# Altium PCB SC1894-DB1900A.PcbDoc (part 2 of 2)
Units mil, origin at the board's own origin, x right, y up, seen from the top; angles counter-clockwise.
Board outline 1800 x 1000 mil, 4 copper layers (L1 TOP, L2 GND, L3 PWR, L4  BOT), stack 35.4 mil thick; 130 components, 74 nets, 300 pads, 606 vias.

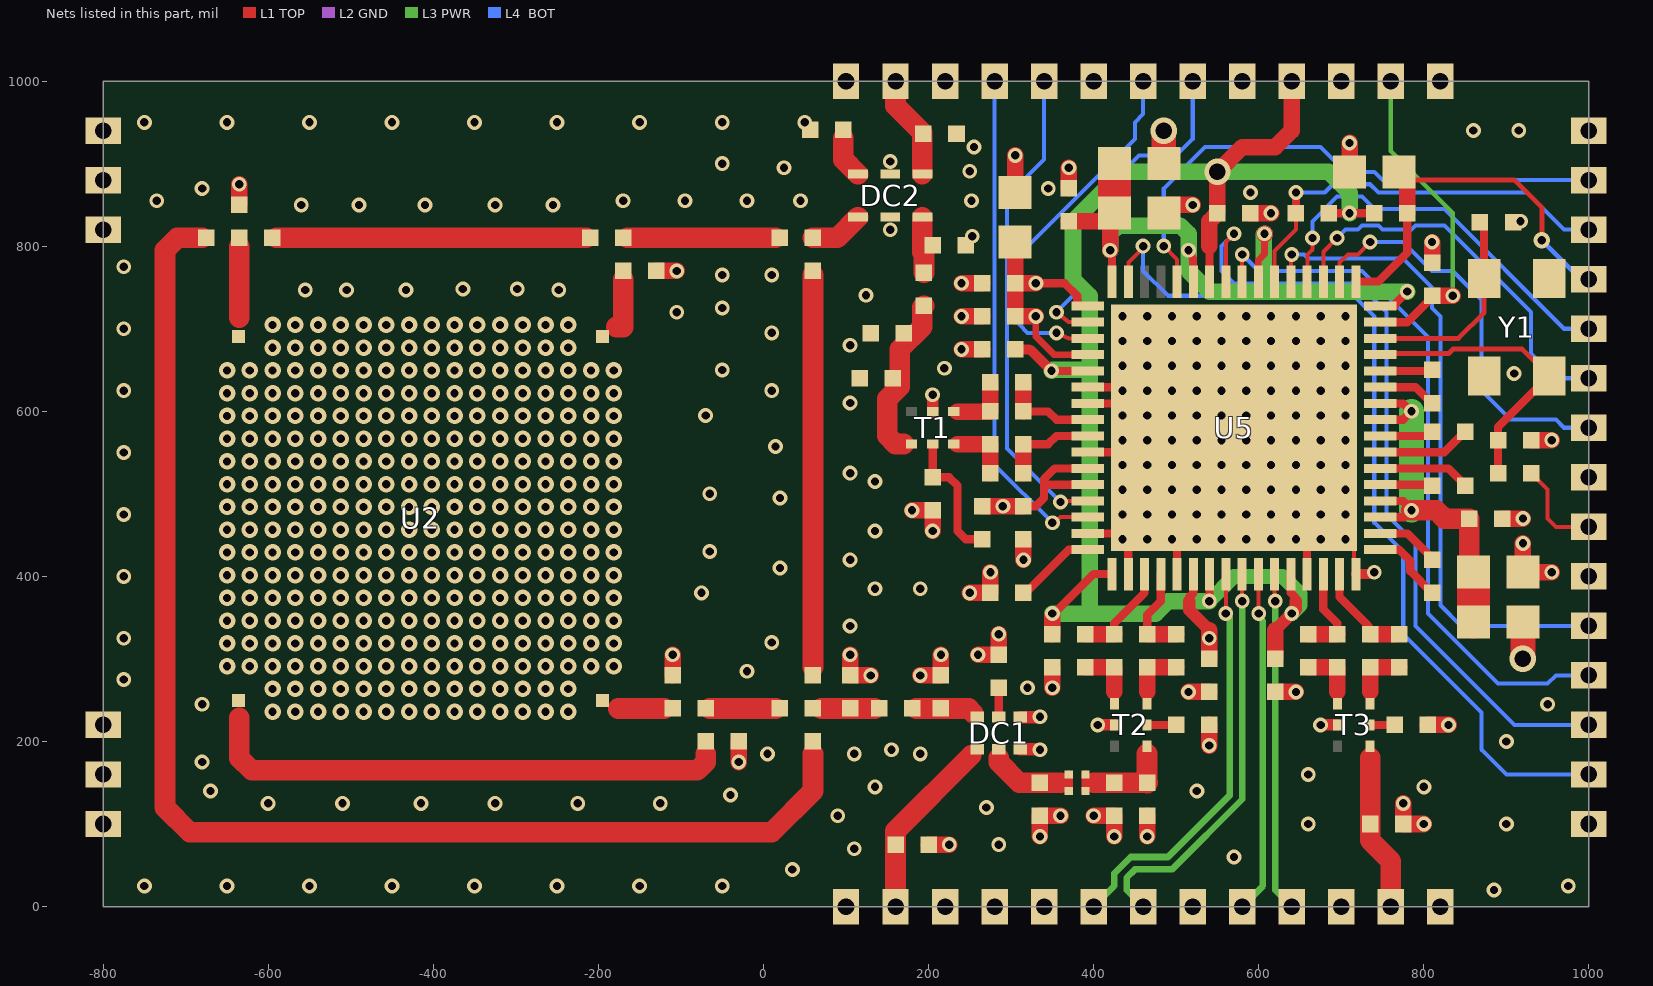
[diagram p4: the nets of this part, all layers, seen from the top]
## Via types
v1: diameter 20, hole 10, L1 TOP to L4  BOT, tented both sides, 308 vias
v2: diameter 18/18/18/18 (per signal layer), hole 10, L1 TOP to L4  BOT, tented both sides, 194 vias
v3: diameter 18/18/18/18 (per signal layer), hole 10, L1 TOP to L4  BOT, 100 vias
v4: diameter 32/32/32/32 (per signal layer), hole 20, L1 TOP to L4  BOT, tented both sides, 3 vias
v5: diameter 20/20/20/20 (per signal layer), hole 10, L1 TOP to L4  BOT, tented both sides, 1 vias

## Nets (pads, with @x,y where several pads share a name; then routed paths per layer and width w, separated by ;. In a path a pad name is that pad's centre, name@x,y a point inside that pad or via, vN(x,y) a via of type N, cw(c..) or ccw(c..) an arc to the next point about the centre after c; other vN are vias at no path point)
+1.8V: C6.1 C8.1 C9.1 C12.1 C31.1 C34.1 FT1.2 FT2.1 FT3.1 P30.1 U5.1 U5.4 U5.11 U5.12 U5.22 U5.47 | length 1125
  L1 TOP w5: C8.1@810,740 C8.1@812.05,740
  L1 TOP w8: v2(330,715) 330,690.58 352,668.58 U5.4@392.83,668.58
  L1 TOP w10: C31.1@315,485 330,485 340,495 340,511.1 ; v2(330,755) 365,755 380,740 380,727.64 U5.1@392.83,727.64 ; U5.12@392.83,511.1 340,511.1 ; U5.11@392.83,530.79 352.8,530.79 340,517.99 340,511.1 ; 515.79,370 515.79,375 520.79,380 U5.22@520.79,402.83 ; U5.47@747.17,707.95 780,707.95 C8.1@812.05,740
  L1 TOP w15: 515.79,370 515.79,359.21 540,335
  L1 TOP w20: FT3.1@265,485 v2(290,485) C31.1@315,485 ; C6.1@305,805 C9.1@305,755 ; v2(330,715) C12.1@305,715 C9.1@305,755 ; v2(330,755) C9.1@305,755 ; C34.1@540,300 v2(540,325) 540,335 ; C8.1@812.05,740 v2(835,740)
  L1 TOP w30: FT1.2@485,900 v4(485,940) ; v4(920,300) FT2.1@920,345
  L3 PWR w5: P30.1@760,1000 760,915 835,840 v2(835,740)
+3.3V: C3.2 C14.1 C33.1 C35.1 P32.1 R1.2 R2.1 U5.5 U5.17 U5.23 U5.28 U5.58 | length 2007.7
  L1 TOP w10: v2(349,649) 349.1,648.9 U5.5@392.83,648.9 ; v2@350,352.49 v2(350,355) 352.17,355 400,402.83 U5.17@422.36,402.83 ; v2(540,370) 540.47,370.47 U5.23@540.47,402.83 ; 540,800 540.47,799.53 U5.58@540.47,757.17 ; U5.28@638.9,402.83 638.9,380 645,373.9 645,370 ; R1.2@685,840 v2(710,840) R2.1@740,840
  L1 TOP w12: C14.1@305,675 321.34,675 322.17,674.17 323.83,674.17 v2(349,649)
  L1 TOP w15: 620,335 v2(640,355) 645,360 645,370
  L1 TOP w20: C33.1@350,330 v2@350,352.49 ; 540,800 540,830 C3.2@550,840 v4(550,890) 580,920 620,920 640,940 P32.1@640,1000 ; C35.1@620,300 620,335
  L3 PWR w18: v2(540,370) 570,400 628.75,400 650,378.75 650,365 v2(640,355)
  L3 PWR w20: v2(349,649) 350,650 395,650 ; v2(350,355) 395,355 ; v2(540,370) 490,370 475,355 395,355 ; v2(710,840) 710,865 685,890 v4(550,890) 435,890 375,830 375,760 395,740 395,650 ; 395,355 395,650
ADCIN0N: P7.1 U5.25 | length 495.6
  L1 TOP w5: U5.25@579.84,402.83 579.84,370 v2(580,370)
  L3 PWR w8: P7.1@460,0 440,20 440,35 450,45 495,45 580,130 v2(580,370)
ADCIN0P: P6.1 U5.24 | length 499.8
  L1 TOP w5: v2(560,355) 560.16,355 U5.24@560.16,402.83
  L3 PWR w8: P6.1@400,0 425,25 425,40 445,60 490,60 565,135 565,350 v2(560,355)
ADCIN1N: P10.1 U5.27 | length 411.9
  L1 TOP w5: U5.27@619.21,402.83 619.21,370 v2(620,370)
  L3 PWR w8: v2(620,370) 620,20 P10.1@640,0
ADCIN1P: P9.1 U5.26 | length 414.8
  L1 TOP w5: U5.26@599.53,402.83 599.53,355 v2(600,355)
  L3 PWR w8: P9.1@580,0 605,25 605,345 v2(600,355)
DGPIN0: P15.1 U5.63 | length 1104.3
  L1 TOP w5: U5.63@442.05,757.17 442.05,780 460,797.95 v2(460,800)
  L4  BOT w5: v2(460,800) 460,770 490,740 715,740 740,715 740,465 775,430 775,330 870,235 870,190 900,160 P15.1@1000,160
DGPIN1: P17.1 U5.56 | length 868.8
  L1 TOP w5: U5.56@579.84,757.17 579.84,790 v2(580,790)
  L4  BOT w5: v2(580,790) 600,770 725,770 805,690 805,355 890,270 950,270 960,280 P17.1@1000,280
EXTCLKIN: C15.2 P20.1 | length 117.4
  L1 TOP w5: C15.2@930,525 950,505 950,470 960,460 P20.1@1000,460
GND: C1.2 C2.1 C3.1 C4.2 C6.2 C8.2 C9.2 C10.2 C11.2 C12.2 C14.2 C22.2 C26.1 C28.1 C29.2 C30.2 C31.2 C33.2 C34.2 C35.2 C36.2 C45.2 C46.2 C47.2 C48.2 DC1.3 DC1.4 DC2.2 DC2.5 P1.1 P3.1 P4.1 P5.1 P8.1 P11.1 P13.1 P14.1 P19.1 P21.1 P28.1 P29.1 P31.1 P33.1 P36.1 P39.1 P41.1 P42.1 P43.1 P44.1 P45.1 P46.1 P47.1 R10.2 R12.1 R13.1 R15.2 R16.2 R21.1 R23.2 R25.2 R27.1 R98.1 R99.1 R104.1 R105.1 T1.5 T2.5 T3.5 U5.6 U5.7 U5.10 U5.15 U5.18 U5.21 U5.29 U5.32 U5.65 Y1.2 Y1.4 | length 2672.5
  L1 TOP w5: v3(705,445) 715.47,445 715.47,405 U5.32@717.64,402.83
  L1 TOP w10: U5.15@392.83,452.05 U5.65@442.05,452.05 ; U5.10@392.83,550.47 U5.65@442.05,550.47 ; U5.7@392.83,609.53 U5.65@570,609.53 ; U5.6@392.83,629.21 495,629.21 570,629.21 U5.65@570,609.53 ; U5.18@442.05,402.83 U5.65@442.05,452.05 ; U5.21@501.1,402.83 U5.65@501.1,452.05 ; U5.29@658.58,402.83 658.58,580 U5.65@570,580 ; U5.65@442.05,452.05 U5.65@501.1,452.05 ; U5.65@442.05,452.05 U5.65@442.05,550.47 ; U5.65@442.05,550.47 U5.65@501.1,550.47 ; U5.65@501.1,452.05 U5.65@501.1,550.47 ; U5.65@501.1,550.47 570,550.47 U5.65@570,580 ; U5.65@501.1,550.47 501.1,580 U5.65@570,580 ; U5.65@570,580 U5.65@570,609.53
  L1 TOP w12: U5.32@717.64,402.83 737.83,402.83 v2(740,405)
  L1 TOP w14: T1.5@205,599.68 v2(205,620) ; v2(405,220) T2.5@425.32,220 ; v2(675,220) T3.5@695.32,220
  L1 TOP w15: DC1.3@310.98,190.51 334.49,190.51 v2(335,190) ; DC1.4@310.98,229.49 334.49,229.49 v2(335,230)
  L1 TOP w20: R98.1@-635,850 v2(-635,875) ; R105.1@-130,770 v2(-105,770) ; R104.1@-110,280 v2(-110,305) ; v2(-30,175) R99.1@-30,200 ; v2(105,305) R13.1@105,280 v2(130,280) ; v2(180,480) C26.1@205,480 v2(205,455) ; v2(190,280) R15.2@215,280 v2(215,305) ; C47.2@200,75 v2(225,75) ; v2(240,675) C14.2@265,675 ; v2(240,715) C12.2@265,715 ; v2(240,755) C9.2@265,755 ; v2(250,380) R12.1@275,380 v2(275,405) ; v2(260,305) R16.2@285,305 v2(285,330) ; C6.2@305,865 v2(305,910) ; v2(315,420) C31.2@315,445 ; v2(335,85) R21.1@335,110 v2(360,110) ; v2(350,265) C33.2@350,290 ; C4.2@370,870 v2(370,895) ; v2(400,110) R23.2@425,110 v2(425,85) ; v2(465,85) C46.2@465,110 ; C2.1@485,840 485,850 v2(520,850) ; v2(515,260) C34.2@540,260 ; v2(540,195) C28.1@540,220 ; C3.1@590,840 v2(615,840) ; C35.2@620,260 v2(645,260) ; C1.2@710,890 v2(710,925) ; v2(775,125) C45.2@775,100 v2(800,100) ; C36.2@805,220 v2(830,220) ; C8.2@810,780 v2(810,805) ; C29.2@895,470 v2(920,470) ; v2(920,440) C30.2@920,405 v2(955,405) ; C11.2@930,565 v2(955,565)
  L2 GND w20: P1.1@100,0 100,1.81 P1.1@100.69,2.5 ; P3.1@219.7,2.5 220,2.2 P3.1@220,0 ; P31.1@700,999.24 P31.1@701.74,997.5 ; P13.1@820,2.33 P13.1@820.17,2.5
  L3 PWR w20: P1.1@100,0 100,1.94 P1.1@100.56,2.5 ; P3.1@220,0 P3.1@220,2.5
  other v1: -594.72,236.06 -567.17,236.06 -539.61,236.06 -512.05,236.06 -484.49,236.06 -456.93,236.06 -429.37,236.06 -401.81,236.06 -374.25,236.06 -346.69,236.06 -319.13,236.06 -291.57,236.06 -264.02,236.06 -236.46,236.06 -594.72,263.62 -567.17,263.62 -539.61,263.62 -512.05,263.62 -484.49,263.62 -456.93,263.62 -429.37,263.62 -401.81,263.62 -374.25,263.62 -346.69,263.62 -319.13,263.62 -291.57,263.62 -264.02,263.62 -236.46,263.62 -649.84,291.18 -622.28,291.18 -594.72,291.18 -567.17,291.18 -539.61,291.18 -512.05,291.18 -484.49,291.18 -456.93,291.18 -429.37,291.18 -401.81,291.18 -374.25,291.18 -346.69,291.18 -319.13,291.18 -291.57,291.18 -264.02,291.18 -236.46,291.18 -208.9,291.18 -181.34,291.18 -649.84,318.74 -622.28,318.74 -594.72,318.74 -567.17,318.74 -539.61,318.74 -512.05,318.74 -484.49,318.74 -456.93,318.74 -429.37,318.74 -401.81,318.74 -374.25,318.74 -346.69,318.74 -319.13,318.74 -291.57,318.74 -264.02,318.74 -236.46,318.74 -208.9,318.74 -181.34,318.74 -649.84,346.3 -622.28,346.3 -594.72,346.3 -567.17,346.3 -539.61,346.3 -512.05,346.3 -484.49,346.3 -456.93,346.3 -429.37,346.3 -401.81,346.3 -374.25,346.3 -346.69,346.3 -319.13,346.3 -291.57,346.3 -264.02,346.3 -236.46,346.3 -208.9,346.3 -181.34,346.3 -649.84,373.86 -622.28,373.86 -594.72,373.86 -567.17,373.86 -539.61,373.86 -512.05,373.86 -484.49,373.86 -456.93,373.86 -429.37,373.86 -401.81,373.86 -374.25,373.86 -346.69,373.86 -319.13,373.86 -291.57,373.86 -264.02,373.86 -236.46,373.86 -208.9,373.86 -181.34,373.86 -649.84,401.42 -622.28,401.42 -594.72,401.42 -567.17,401.42 -539.61,401.42 -512.05,401.42 -484.49,401.42 -456.93,401.42 -429.37,401.42 -401.81,401.42 -374.25,401.42 -346.69,401.42 -319.13,401.42 -291.57,401.42 -264.02,401.42 -236.46,401.42 -208.9,401.42 -181.34,401.42 -649.84,428.98 -622.28,428.98 -594.72,428.98 -567.17,428.98 -539.61,428.98 -512.05,428.98 -484.49,428.98 -456.93,428.98 -429.37,428.98 -401.81,428.98 -374.25,428.98 -346.69,428.98 -319.13,428.98 -291.57,428.98 -264.02,428.98 -236.46,428.98 -208.9,428.98 -181.34,428.98 -649.84,456.54 -622.28,456.54 -594.72,456.54 -567.17,456.54 -539.61,456.54 -512.05,456.54 -484.49,456.54 -456.93,456.54 -429.37,456.54 -401.81,456.54 -374.25,456.54 -346.69,456.54 -319.13,456.54 -291.57,456.54 -264.02,456.54 -236.46,456.54 -208.9,456.54 -181.34,456.54 -649.84,484.09 -622.28,484.09 -594.72,484.09 -567.17,484.09 -539.61,484.09 -512.05,484.09 -484.49,484.09 -456.93,484.09 -429.37,484.09 -401.81,484.09 -374.25,484.09 -346.69,484.09 -319.13,484.09 -291.57,484.09 -264.02,484.09 -236.46,484.09 -208.9,484.09 -181.34,484.09 -649.84,511.65 -622.28,511.65 -594.72,511.65 -567.17,511.65 -539.61,511.65 -512.05,511.65 -484.49,511.65 -456.93,511.65 -429.37,511.65 -401.81,511.65 -374.25,511.65 -346.69,511.65 -319.13,511.65 -291.57,511.65 -264.02,511.65 -236.46,511.65 -208.9,511.65 -181.34,511.65 -649.84,539.21 -622.28,539.21 -594.72,539.21 -567.17,539.21 -539.61,539.21 -512.05,539.21 -484.49,539.21 -456.93,539.21 -429.37,539.21 -401.81,539.21 -374.25,539.21 -346.69,539.21 -319.13,539.21 -291.57,539.21 -264.02,539.21 -236.46,539.21 -208.9,539.21 -181.34,539.21 -649.84,566.77 -622.28,566.77 -594.72,566.77 -567.17,566.77 -539.61,566.77 -512.05,566.77 -484.49,566.77 -456.93,566.77 -429.37,566.77 -401.81,566.77 -374.25,566.77 -346.69,566.77 -319.13,566.77 -291.57,566.77 -264.02,566.77 -236.46,566.77 -208.9,566.77 -181.34,566.77 -649.84,594.33 -622.28,594.33 -594.72,594.33 -567.17,594.33 -539.61,594.33 -512.05,594.33 -484.49,594.33 -456.93,594.33 -429.37,594.33 -401.81,594.33 -374.25,594.33 -346.69,594.33 -319.13,594.33 -291.57,594.33 -264.02,594.33 -236.46,594.33 -208.9,594.33 -181.34,594.33 -649.84,621.89 -622.28,621.89 -594.72,621.89 -567.17,621.89 -539.61,621.89 -512.05,621.89 -484.49,621.89 -456.93,621.89 -429.37,621.89 -401.81,621.89 -374.25,621.89 -346.69,621.89 -319.13,621.89 -291.57,621.89 -264.02,621.89 -236.46,621.89 -208.9,621.89 -181.34,621.89 -649.84,649.45 -622.28,649.45 -594.72,649.45 -567.17,649.45 -539.61,649.45 -512.05,649.45 -484.49,649.45 -456.93,649.45 -429.37,649.45 -401.81,649.45 -374.25,649.45 -346.69,649.45 -319.13,649.45 -291.57,649.45 -264.02,649.45 -236.46,649.45 -208.9,649.45 -181.34,649.45 -594.72,677.01 -567.17,677.01 -539.61,677.01 -512.05,677.01 -484.49,677.01 -456.93,677.01 -429.37,677.01 -401.81,677.01 -374.25,677.01 -346.69,677.01 -319.13,677.01 -291.57,677.01 -264.02,677.01 -236.46,677.01 -594.72,704.57 -567.17,704.57 -539.61,704.57 -512.05,704.57 -484.49,704.57 -456.93,704.57 -429.37,704.57 -401.81,704.57 -374.25,704.57 -346.69,704.57 -319.13,704.57 -291.57,704.57 -264.02,704.57 -236.46,704.57
  other v2: 885,20 -750,25 -650,25 -550,25 -450,25 -350,25 -250,25 -150,25 -50,25 975,25 35,45 570,60 110,70 285,75 660,100 900,100 90,110 270,120 -600,125 -510,125 -415,125 -325,125 -225,125 -125,125 -40,135 -670,140 525,140 135,145 800,145 660,160 -680,175 5,185 110,185 190,185 155,190 900,200 -680,245 950,245 320,265 -775,275 -20,285 10,320 -775,325 105,340 -75,380 135,385 190,385 -775,400 20,410 105,420 -65,430 135,455 -775,475 20,495 -65,500 135,515 105,525 -775,550 14.69,557.28 -70,595 105,610 -775,625 10,625 909.45,645.67 -50,650 219.17,652.05 105,680 10,695 -775,700 -105,720 -50,725 124.09,740.59 -555.12,747.05 -504.92,747.05 -433.07,747.05 -248.03,747.05 -364.17,748.03 -298.23,748.03 -50,765 10,765 -775,775 252.95,812.01 153.54,819.88 917.24,830.16 -560,850 -490,850 -410,850 -325,850 -255,850 -735,855 -170,855 -95,855 -20,855 45,855 252.05,855.08 590,865 -680,870 345,870 250,890.75 25,895 -50,900 153.54,902.56 255,920 860,940 915,940 -750,950 -650,950 -550,950 -450,950 -350,950 -250,950 -150,950 -50,950 50,950
  other v3: 435,445 465,445 495,445 525,445 555,445 585,445 615,445 645,445 675,445 435,475 465,475 495,475 525,475 555,475 585,475 615,475 645,475 675,475 705,475 435,505 465,505 495,505 525,505 555,505 585,505 615,505 645,505 675,505 705,505 435,535 465,535 495,535 525,535 555,535 585,535 615,535 645,535 675,535 705,535 435,565 465,565 495,565 525,565 555,565 585,565 615,565 645,565 675,565 705,565 435,595 465,595 495,595 525,595 555,595 585,595 615,595 645,595 675,595 705,595 435,625 465,625 495,625 525,625 555,625 585,625 615,625 645,625 675,625 705,625 435,655 465,655 495,655 525,655 555,655 585,655 615,655 645,655 675,655 705,655 435,685 465,685 495,685 525,685 555,685 585,685 615,685 645,685 675,685 705,685 435,715 465,715 495,715 525,715 555,715 585,715 615,715 645,715 675,715 705,715
LOADENB: P27.1 U5.60 | length 671.8
  L1 TOP w5: v2(485,800) 500.36,784.64 500.36,784.25 501.1,783.51 U5.60@501.1,757.17
  L4  BOT w5: v2(485,800) 485,870 535,920 675,920 705,890 740,890 750,880 P27.1@1000,880
MGPO0: P34.1 U5.2 | length 416.8
  L1 TOP w5: v2(355,720) 370,707.95 U5.2@392.83,707.95
  L4  BOT w5: v2(355,720) 380,745 380,835 455,910 500,910 520,930 P34.1@520,1000
MGPO1: P35.1 U5.3 | length 445.6
  L1 TOP w5: v2(355,695) 370,688.27 U5.3@392.83,688.27
  L4  BOT w5: v2(355,695) 320,695 310,705 310,790 450,930 450,950 460,960 P35.1@460,1000
MGPO2: P37.1 U5.13 | length 589.8
  L1 TOP w5: v2(360,490) 360,491.42 U5.13@392.83,491.42
  L4  BOT w5: P37.1@340,1000 340,905 295,860 295,555 v2(360,490)
MGPO3: P38.1 U5.14 | length 608.9
  L1 TOP w5: v2(350,465) 360,471.73 U5.14@392.83,471.73
  L4  BOT w5: P38.1@280,1000 280,535 v2(350,465)
N16778023: C11.1 C15.1 U5.45 Y1.3 | length 365.1
  L1 TOP w6: U5.45@747.17,668.58 747.17,670 830,670 835.34,675.34 919.15,675.34 Y1.3@951.77,642.72
  L1 TOP w10: C15.1@890,525 C11.1@890,565 890,580.94 Y1.3@951.77,642.72
N16778042: C29.1 C30.1 FT2.2 U5.35 U5.36 U5.41 U5.42 | length 499.8
  L1 TOP w10: U5.35@747.17,471.73 776.73,471.73 v2(785,480) 785,481.42 775,491.42 U5.36@747.17,491.42 ; U5.41@747.17,589.84 775,589.84 775,590 v2(785,600) 784.53,600 775,609.53 U5.42@747.17,609.53
  L1 TOP w25: v2(785,480) 815,480 825,470 C29.1@855,470 855,400 C30.1@860,405
  L1 TOP w40: FT2.2@860,345 C30.1@860,405
  L3 PWR w30: v2(785,480) v2(785,600)
N16778055: L1.2 L2.2 U5.8 | length 117
  L1 TOP w10: L1.2@315,600 315.16,599.84 345,599.84 355,589.84 U5.8@392.83,589.84
  L1 TOP w20: L1.2@315,600 L2.2@315,635
N16778107: L4.2 L6.1 U5.20 | length 114.6
  L1 TOP w10: L4.2@465,330 465,353.58 481.42,370 U5.20@481.42,402.83
  L1 TOP w20: L4.2@465,330 L6.1@500,330
N16778109: C2.2 C4.1 FT1.1 U5.48 U5.55 U5.59 U5.64 | length 924.4
  L1 TOP w8: U5.55@599.53,757.17 599.53,783 607,790.47 v2@607,814.24
  L1 TOP w10: v2@420,802.36 420.98,795.13 421,795 422.36,785 U5.64@422.36,757.17 ; v2(515,795) 520.46,785.01 520.46,760.33 520.79,760 U5.59@520.79,757.17 ; U5.48@747.17,727.64 765,727.64 765,730 v2(780,745)
  L1 TOP w20: C4.1@370,830 C2.2@420,830 ; v2(420,795) 420,802.36 C2.2@420,830 ; C2.2@425,840 420,835 C2.2@420,830 ; FT1.1@425,895 FT1.1@425,900 ; v2@607,814.24 v2(607,815)
  L1 TOP w40: C2.2@425,840 FT1.1@425,895
  L3 PWR w20: v2(420,795) 420,815 430,825 505,825 515,815 v2(515,795) 515,769.99 539.99,744.99 ; v2(607,815) 606.29,814.29 606.29,744.99 ; v2(780,745) 775,745 606.29,744.99 ; 540,744.99 606.29,744.99 ; 539.99,744.99 606.29,744.99
N16778151: R11.2 R13.2 R14.2 R17.1 R101.1 | length 80
  L1 TOP w5: R17.1@60,240 70,240 ; R14.2@135,240 R14.2@140,240
  L1 TOP w25: 70,240 R13.2@105,240 R14.2@135,240
N16778208: C10.1 U5.46 Y1.1 | length 250.4
  L1 TOP w6: U5.46@747.17,688.27 841.81,688.27 873.03,719.49 Y1.1@873.03,760.83
  L1 TOP w10: C10.1@868.03,828.98 873.03,823.98 Y1.1@873.03,760.83
N16778332: C22.1 R25.1 R26.1 T1.1 | length 209.5
  L1 TOP w10: 170,560.32 T1.1@179.41,560.32
  L1 TOP w25: 170,560.32 160,560.32 150,570.32 150,615 165,630 165,675 192.54,702.54 192.54,725.96 R26.1@194.45,727.87
N16778603: C26.2 FT3.2 T1.2 | length 163.6
  L1 TOP w10: T1.2@205,560.32 C26.2@205,520 225,520 235,510 235,455 245,445 FT3.2@265,445
N16778643: DC1.2 R21.2 R22.2 R24.2 | length 130.9
  L1 TOP w5: 285,180 DC1.2@285,190.51
  L1 TOP w10: 360,150 370,150 ; R24.2@370,140 370,150 ; R22.2@370,160 370,150
  L1 TOP w25: 285,180 285,175 310,150 R21.2@335,150 360,150
N16778760: R12.2 U5.16 | length 99.5
  L1 TOP w10: R12.2@315,380 317.64,380 370,432.36 U5.16@392.83,432.36
N16778848: L7.2 L8.1 U5.31 | length 123.2
  L1 TOP w10: U5.31@697.95,402.83 697.95,375 732.95,340 732.95,332.05 L7.2@735,330 ; L8.1@765,330 L8.1@770,330
  L1 TOP w20: L7.2@735,330 L8.1@765,330
N16778850: DC1.6 R14.1 R15.1 | length 88.4
  L1 TOP w5: R14.1@180,240 R14.1@185,240 ; DC1.6@254.25,234.25 DC1.6@259.02,229.49
  L1 TOP w25: R14.1@185,240 R15.1@210,240 ; R15.1@215,240 R15.1@210,240 ; DC1.6@254.25,234.25 248.5,240 R15.1@210,240
N16778878: L7.1 L9.2 U5.30 | length 114.8
  L1 TOP w10: U5.30@678.27,402.83 678.27,360 695,343.27 L7.1@695,330
  L1 TOP w20: L9.2@660,330 L7.1@695,330
N16778883: C46.1 R22.1 R23.1 R24.1 T2.1 | length 154.5
  L1 TOP w5: 464.68,185 T2.1@464.68,194.41
  L1 TOP w10: R24.1@390,140 390,150 ; R22.1@390,160 390,150 ; 400,150 390,150
  L1 TOP w25: 400,150 440,150 ; R23.1@425,150 440,150 ; C46.1@464.68,150.32 464.68,185 ; C46.1@465,150 440,150
  L1 TOP w26: C46.1@464.68,150.32 C46.1@465,150
N16778928: C36.1 T3.2 | length 30.3
  L1 TOP w10: T3.2@734.68,220 C36.1@765,220
N16778955: C17.1 L2.1 T1.4 | length 79.5
  L1 TOP w12: T1.4@230.59,599.68 T1.4@235,599.68
  L1 TOP w20: T1.4@235,599.68 274.68,599.68 C17.1@275,600 L2.1@275,635
N16779024: L1.1 L3.1 U5.9 | length 117
  L1 TOP w10: L1.1@315,560 315.16,560.16 345,560.16 355,570.16 U5.9@392.83,570.16
  L1 TOP w20: L3.1@315,525 L1.1@315,560
N16779035: L4.1 L5.2 U5.19 | length 123
  L1 TOP w10: L4.1@425,330 425,343.27 461.73,380 U5.19@461.73,402.83
  L1 TOP w20: L5.2@390,330 L4.1@425,330
N16779186: C28.2 T2.2 | length 35.3
  L1 TOP w10: T2.2@464.68,220 C28.2@500,220
N16779383: C18.1 L5.1 T2.4 | length 79.5
  L1 TOP w8: 425,260 425.32,259.68 T2.4@425.32,245.59
  L1 TOP w20: L5.1@390,290 C18.1@425,290 425,260
N16779385: C18.2 L6.2 T2.3 | length 79.5
  L1 TOP w8: T2.3@464.68,245.59 464.68,259.68 465,260
  L1 TOP w20: 465,260 C18.2@465,290 L6.2@500,290
N16779627: C13.1 U5.44 | length 63.3
  L1 TOP w10: U5.44@747.17,648.9 808.9,648.9 C13.1@810,650
N16779631: C13.2 U5.43 | length 70.8
  L1 TOP w10: U5.43@747.17,629.21 790,629.21 809.21,610 C13.2@810,610
N16779697: C25.1 U5.40 | length 64.8
  L1 TOP w10: U5.40@747.17,570.16 805.16,570.16 C25.1@810,575
N16779756: C25.2 U5.39 | length 113
  L1 TOP w10: U5.39@747.17,550.47 825,550.47 849.53,575 C25.2@850,575
N16779783: C27.1 U5.38 | length 111.9
  L1 TOP w10: U5.38@747.17,530.79 830,530.79 850,510.79 C27.1@850,510
N16779788: DC2.6 R10.1 | length 51.3
  L1 TOP w25: R10.1@96.84,931.15 96.84,904.92 DC2.6@114.54,887.22
N16779793: C27.2 U5.37 | length 63.9
  L1 TOP w10: U5.37@747.17,511.1 810,511.1 C27.2@810,510
N16779834: C32.1 U5.34 | length 77.3
  L1 TOP w10: U5.34@747.17,452.05 780,452.05 810,422.05 C32.1@810,420
N16779938: C32.2 U5.33 | length 91.8
  L1 TOP w10: U5.33@747.17,432.36 770,432.36 783.68,418.68 783.68,406.32 C32.2@810,380
N16779945: DC1.5 R16.1 | length 35.5
  L1 TOP w10: DC1.5@285,229.49 R16.1@285,265
N16780104: C20.1 L9.1 T3.4 | length 79.5
  L1 TOP w8: 695,260 695.32,259.68 T3.4@695.32,245.59
  L1 TOP w20: L9.1@660,290 C20.1@695,290 695,260
N16780111: C20.2 L8.2 T3.3 | length 79.5
  L1 TOP w8: T3.3@734.68,245.59 734.68,259.68 735,260
  L1 TOP w20: 735,260 C20.2@735,290 L8.2@770,290
N16780228: C17.2 L3.2 T1.3 | length 79.5
  L1 TOP w12: T1.3@230.59,560.32 T1.3@235,560.32
  L1 TOP w20: T1.3@235,560.32 274.68,560.32 C17.2@275,560 L3.2@275,525
N16798679: R102.2 R105.2 U2.2 | length 76
  L1 TOP w5: R105.2@-170,760 R105.2@-170,770
  L1 TOP w25: -178,702 -170,702 R105.2@-170,760
N16798683: R97.1 R104.2 U2.1 | length 66
  L1 TOP w5: R97.1@-120,240 R97.1@-110,240
  L1 TOP w25: -176,240 R97.1@-120,240
N16798687: R96.1 R99.2 U2.4 | length 648.7
  L1 TOP w5: -70,185 R99.2@-70,200
  L1 TOP w25: -635,228.35 -635,180 -620,165 -80,165 -70,175 -70,185
N16798691: R95.2 R98.2 R100.2 U2.3 | length 96.4
  L1 TOP w5: R98.2@-635,800 R98.2@-635,810
  L1 TOP w25: -635,713.58 R98.2@-635,800
N16798746: R8.2 R102.1 R103.1 | length 190
  L1 TOP w5: R103.1@-170,810 R103.1@-165,810 ; R8.2@15,810 R8.2@20,810
  L1 TOP w25: R103.1@-165,810 R8.2@15,810
N16798748: DC2.1 R8.1 R9.2 | length 65
  L1 TOP w25: R9.2@60,810 89.31,810 DC2.1@114.54,835.22
N16798750: R100.1 R103.2 | length 385
  L1 TOP w5: R100.1@-595,810 R100.1@-590,810 ; R103.2@-215,810 R103.2@-210,810
  L1 TOP w25: R100.1@-590,810 R103.2@-215,810
N16798758: R17.2 R96.2 R97.2 | length 95.7
  L1 TOP w5: R97.2@-72.68,235 R97.2@-70,240 R97.2@-65,240 ; R17.2@15,240 R17.2@20,240
  L1 TOP w25: R97.2@-65,240 R17.2@15,240
N16798802: R95.1 R101.2 | length 1609.4
  L1 TOP w5: R95.1@-680,810 R95.1@-675,810 ; 60,185 R101.2@60,200
  L1 TOP w25: R95.1@-680,810 -710,810 -725,795 -725,120 -695,90 10,90 60,140 60,185
N16798852: R9.1 R11.1 | length 490
  L1 TOP w5: R11.1@60,280 60,290 ; R9.1@60,765 R9.1@60,770
  L1 TOP w25: 60,290 R9.1@60,765
N16798884: 
N16798892: 
N16798938: 
RESETN: C1.1 P25.1 R2.2 U5.49 | length 483.1
  L1 TOP w5: C1.1@775.6,880 C1.1@780,880
  L1 TOP w6: C1.1@780,880 910,880 942.91,847.09 v5(942.91,807.09)
  L1 TOP w10: U5.49@717.64,757.17 745,757.17 780,792.17 R2.2@780,833.6 ; C1.1@770,890 C1.1@775.6,880
  L1 TOP w20: C1.1@775.6,880 776.8,887.2 780,884 780,880 R2.2@780,840
  L4  BOT w6: v5(942.91,807.09) 990,760 P25.1@1000,760
RFFB: C45.1 P12.1 T3.1 | length 205
  L1 TOP w5: T3.1@734.68,194.41 734.68,180.32 735,180
  L1 TOP w20: 735,80.14 737,78.14
  L1 TOP w25: 735,80.14 C45.1@735,100 735,180 ; 737,78.14 760.14,55 760.14,29.97 P12.1@760,0
RFIN: C47.1 DC1.1 P2.1 | length 231.5
  L1 TOP w5: 251.82,183.31 DC1.1@259.02,190.51
  L1 TOP w25: P2.1@160,0 C47.1@160,75 160,91.5 251.82,183.31
RFOUT: C48.1 DC2.4 P40.1 | length 126.3
  L1 TOP w25: P40.1@160,1000 160,969.97 192.54,937.43 DC2.4@192.54,887.22
RFOUT_Cor_Cpl: DC2.3 R26.2 R27.2 | length 68.1
  L1 TOP w25: DC2.3@192.54,835.22 192.54,792.43 194.45,790.51 R26.2@194.45,767.87
SCLK: P23.1 U5.51 | length 481
  L1 TOP w5: U5.51@678.27,757.17 678.27,793.27 v2(695,810)
  L4  BOT w5: v2(695,810) 705,820 720,820 725,825 745,825 750,820 785,820 790,825 825,825 930,720 930,670 960,640 P23.1@1000,640
SDI: P18.1 U5.53 | length 800
  L1 TOP w5: U5.53@638.9,757.17 638.9,790 v2(640,790)
  L4  BOT w5: v2(640,790) 655,790 660,785 775,785 810,750 810,725 820,715 820,365 845,340 P18.1@1000,340
SDO: P26.1 R1.1 U5.54 | length 500.4
  L1 TOP w5: U5.54@619.21,757.17 619.21,794.21 645,820 R1.1@645,840
  L1 TOP w10: R1.1@645,840 v2(645,865)
  L4  BOT w5: v2(645,865) 680,865 690,875 735,875 745,865 925,865 970,820 P26.1@1000,820
SSN: P24.1 U5.52 | length 489.2
  L1 TOP w5: U5.52@658.58,757.17 658.58,760 659.29,760.71 659.29,790 665,795.71 v2(665,810)
  L4  BOT w5: v2(665,810) 665,830 695,860 725,860 740,845 825,845 970,700 P24.1@1000,700
STATO: P16.1 U5.57 | length 988
  L1 TOP w5: U5.57@560.16,757.17 560.16,805 570,814.84 v2(570,815)
  L4  BOT w5: v2(570,815) 555,800 555,770 570,755 720,755 755,720 755,475 790,440 790,340 910,220 P16.1@1000,220
WDTENB: P22.1 U5.50 | length 492.9
  L1 TOP w5: U5.50@697.95,757.17 697.95,780 707.95,790 720,790 v2(735,805)
  L4  BOT w5: v2(735,805) 775,805 810,770 835,770 870,735 870,625 905,590 960,590 970,580 P22.1@1000,580
pads on no net: T1.6 T2.6 T3.6 U5.61 U5.62

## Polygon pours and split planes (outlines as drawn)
GND on L3 PWR "L3 PWR-GND" (solid, remove dead copper, pour order 4): -790,990 250,990 250,260 990,260 990,10 -790,10
+1.8V on L3 PWR "L3 PWR-+1.8V" (solid, remove dead copper, pour order 2): 260,990 990,990 990,270 260,270
GND on L4  BOT "L4  BOT-GND" (solid, remove dead copper, pour order 8): -790,990 990,990 990,10 -790,10
GND on L2 GND "L2 GND-GND" (solid, remove dead copper, pour order 10): -790,990 990,990 990,10 -790,10
GND on L1 TOP "L1 TOP-GND" (solid, remove dead copper, pour order 6): -790,990 990,990 990,10 -790,10

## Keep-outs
Keep-Out Layer:
  the board outline again, w1

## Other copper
L1 TOP:
  rectangle net N16798687: -643.7,221.46 -627.95,257.87
  rectangle net N16798691: -643.7,683.07 -627.95,730.32
  rectangle net N16798679: -202.76,683.07 -157.48,700.79
  region net GND: 831,965 809,965 809,1000 831,1000 831,965
  region net GND: 231,965 209,965 209,1000 231,1000 231,965
  region net GND: 711,965 689,965 689,1000 711,1000 711,965
  region net GND: 831,0 809,0 809,35 831,35 831,0
  region net GND: 1000,951 1000,929 965,929 965,951 1000,951
  region net GND: 411,965 389,965 389,1000 411,1000 411,965
  region net GND: -765,951 -765,929 -800,929 -800,951 -765,951
  region net GND: 1000,411 1000,389 965,389 965,411 1000,411
  region net GND: -765,831 -765,809 -800,809 -800,831 -765,831
  region net GND: 591,965 569,965 569,1000 591,1000 591,965
  region net GND: 231,0 209,0 209,35 231,35 231,0
  region net GND: 711,0 689,0 689,35 711,35 711,0
  region net GND: 111,965 89,965 89,1000 111,1000 111,965
  region net GND: 111,0 89,0 89,35 111,35 111,0
  region net GND: -765,111 -765,89 -800,89 -800,111 -765,111
  region net GND: -765,891 -765,869 -800,869 -800,891 -765,891
  region net GND: 351,0 329,0 329,35 351,35 351,0
  region net GND: 291,0 269,0 269,35 291,35 291,0
  region net GND: 1000,531 1000,509 965,509 965,531 1000,531
  region net GND: 1000,111 1000,89 965,89 965,111 1000,111
  region net GND: -765,231 -765,209 -800,209 -800,231 -765,231
  region net GND: -765,171 -765,149 -800,149 -800,171 -765,171
  region net GND: 531,0 509,0 509,35 531,35 531,0
  region net GND: 144.68,819.88 142.72,820.87 141.73,821.85 141.73,830.71 165.35,830.71 165.35,821.85 162.4,819.88
  region net GND: 141.72,892.15 141.72,900.02 144.68,902.97 162.39,902.97 165.35,900.02 165.35,892.15
  region net GND: -669.29,671.26 -669.29,269.68 -600.63,269.68 -600.63,203.74 -214.57,203.74 -214.57,269.68 -187.01,269.68 -187.01,280.51 -157.48,280.51 -157.48,664.37 -187.01,664.37 -187.01,671.26 -214.57,671.26 -214.57,760.83 -602.36,760.83 -602.36,671.26
  region net N16798683: -202.76,257.87 -187.01,257.87 -175.2,246.06 -175.2,230.32 -177.17,230.32 -202.76,255.91
  text "L1 TOP" at 55.91,-778.15 h50
L2 GND:
  rectangle net GND: -694.88,202.76 -115.16,750.98
  region net GND: 965,929 965,951 1000,951 1000,929 965,929
  region net GND: 965,389 965,411 1000,411 1000,389 965,389
  region net GND: -800,209 -800,231 -765,231 -765,209 -800,209
  region net GND: 711,965 689,965 689,1000 711,1000 711,965
  region net GND: 231,965 209,965 209,1000 231,1000 231,965
  region net GND: -800,929 -800,951 -765,951 -765,929 -800,929
  region net GND: 711,0 689,0 689,35 711,35 711,0
  region net GND: 831,0 809,0 809,35 831,35 831,0
  region net GND: -800,149 -800,171 -765,171 -765,149 -800,149
  region net GND: 591,965 569,965 569,1000 591,1000 591,965
  region net GND: 531,0 509,0 509,35 531,35 531,0
  region net GND: 831,965 809,965 809,1000 831,1000 831,965
  region net GND: 965,89 965,111 1000,111 1000,89 965,89
  region net GND: 291,0 269,0 269,35 291,35 291,0
  region net GND: 111,965 89,965 89,1000 111,1000 111,965
  region net GND: 111,0 89,0 89,35 111,35 111,0
  region net GND: -800,89 -800,111 -765,111 -765,89 -800,89
  region net GND: 1000,531 1000,509 965,509 965,531 1000,531
  region net GND: -800,869 -800,891 -765,891 -765,869 -800,869
  region net GND: 231,0 209,0 209,35 231,35 231,0
  region net GND: -800,809 -800,831 -765,831 -765,809 -800,809
  region net GND: 351,0 329,0 329,35 351,35 351,0
  region net GND: 411,965 389,965 389,1000 411,1000 411,965
  text "L2 GND" at 55.91,-778.15 h50
L3 PWR:
  rectangle net GND: -697.83,191.93 -113.19,750.98
  region net GND: -800,89 -800,111 -765,111 -765,89 -800,89
  region net GND: 209,1000 231,1000 231,965 209,965 209,1000
  region net GND: 89,1000 111,1000 111,965 89,965 89,1000
  region net +1.8V: 744,1000 776,1000 776,945 744,945 744,1000
  region net GND: -800,209 -800,231 -765,231 -765,209 -800,209
  region net GND: -800,929 -800,951 -765,951 -765,929 -800,929
  region net GND: 89,35 111,35 111,0 89,0 89,35
  region net GND: 329,35 351,35 351,0 329,0 329,35
  region net GND: 389,1000 411,1000 411,965 389,965 389,1000
  region net GND: -800,149 -800,171 -765,171 -765,149 -800,149
  region net GND: -800,869 -800,891 -765,891 -765,869 -800,869
  region net GND: 209,35 231,35 231,0 209,0 209,35
  region net GND: 965,89 965,111 1000,111 1000,89 965,89
  region net GND: 269,35 291,35 291,0 269,0 269,35
  region net GND: -800,809 -800,831 -765,831 -765,809 -800,809
  region net GND: 809,35 831,35 831,0 809,0 809,35
  region net GND: 689,35 711,35 711,0 689,0 689,35
  region net GND: 509,35 531,35 531,0 509,0 509,35
  text "L3 PWR" at 55.91,-778.15 h50
L4  BOT:
  rectangle net GND: -678.15,202.76 -155.51,734.25
  region net GND: 804,35 836,35 836,0 804,0 804,35
  region net GND: 965,924 965,956 1000,956 1000,924 965,924
  region net GND: 965,84 965,116 1000,116 1000,84 965,84
  region net GND: -800,144 -800,176 -765,176 -765,144 -800,144
  region net GND: 564,1000 596,1000 596,965 564,965 564,1000
  region net GND: 264,35 296,35 296,0 264,0 264,35
  region net GND: 84,35 116,35 116,0 84,0 84,35
  region net GND: 965,504 965,536 1000,536 1000,504 965,504
  region net GND: -800,204 -800,236 -765,236 -765,204 -800,204
  region net GND: -800,804 -800,836 -765,836 -765,804 -800,804
  region net GND: -800,864 -800,896 -765,896 -765,864 -800,864
  region net GND: 204,35 236,35 236,0 204,0 204,35
  region net GND: 84,1000 116,1000 116,965 84,965 84,1000
  region net GND: 684,35 716,35 716,0 684,0 684,35
  region net GND: 204,1000 236,1000 236,965 204,965 204,1000
  region net GND: 684,1000 716,1000 716,965 684,965 684,1000
  region net GND: 504,35 536,35 536,0 504,0 504,35
  region net GND: 384,1000 416,1000 416,965 384,965 384,1000
  region net GND: 324,35 356,35 356,0 324,0 324,35
  region net GND: -800,84 -800,116 -765,116 -765,84 -800,84
  region net GND: -800,924 -800,956 -765,956 -765,924 -800,924
  region net GND: 804,1000 836,1000 836,965 804,965 804,1000
  region net GND: 965,384 965,416 1000,416 1000,384 965,384
  text "RDB3.6 REV2" at -725,365 h25 r270
  text "L4 BOT" at 55.91,-778.15 h50
Multi-Layer:
  text "SCINTERA" at 50,-300 h50
  text "SC1894-DB1900A ASSEMBLY DRAWING" at 55.91,-445.67 h50
  text "(RDB3.6 REV2)" at 55.91,-628.15 h50

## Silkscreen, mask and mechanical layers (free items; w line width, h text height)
Silkscreen Top:
  region: 840,265 960,265 960,40 840,40 840,265
  region: 80,60 120,60 100,30 80,60
  text "SCINTERA" at -610,905 h25
  text "RDB3.6 REV2" at -385,905 h25
  text "SILK TOP" at 55.91,-778.15 h50
Paste Mask Top:
  text "PASTE TOP" at 55.91,-778.15 h50
Solder Mask Top:
  region: -565,840 -240,840 -240,780 -565,780 -565,840
  region: 40,180 85,180 85,130 15,60 -705,60 -750,105 -750,805 -720,835 -695,835 -695,135 -680,120 5,120 40,155 40,180
  region: 225,180 255,150 185,80 185,25 135,25 135,105 215,185 225,185 225,180
  region: -120,840 -120,785 5,785 5,840 -120,840
  region: 35,745 80,745 80,305 35,305 35,745
  region: -95,195 -95,140 -660,140 -660,195 -95,195
  region: 715,115 755,115 755,90 780,65 780,15 740,15 740,50 715,75 715,115
  text "SOLDERMASK TOP" at 55.91,-778.15 h50
Solder Mask Bottom:
  region: 650,575 715,575 715,510 650,510 650,575
  region: 500,500 565,500 565,435 500,435 500,500
  region: 650,650 715,650 715,585 650,585 650,650
  region: 425,575 490,575 490,510 425,510 425,575
  region: 575,650 640,650 640,585 575,585 575,650
  region: 650,500 715,500 715,435 650,435 650,500
  region: 575,575 640,575 640,510 575,510 575,575
  region: 575,725 640,725 640,660 575,660 575,725
  region: 425,500 490,500 490,435 425,435 425,500
  region: 425,650 490,650 490,585 425,585 425,650
  region: 425,725 490,725 490,660 425,660 425,725
  region: 500,725 565,725 565,660 500,660 500,725
  region: 500,575 565,575 565,510 500,510 500,575
  region: 500,650 565,650 565,585 500,585 500,650
  region: 575,500 640,500 640,435 575,435 575,500
  region: 650,725 715,725 715,660 650,660 650,725
  text "SOLDERMASK BOT" at 55.91,-778.15 h50
Assembly Drawing Top:
  lines w5: -558.12,1369.08 -77.42,1369.08 ; -552.74,1378.04 -93.99,1378.04 ; -547.37,1387 -305,1387 ; -541.99,1395.96 -314.41,1395.96 ; -537.06,1404.92 -378.47,1404.92 ; -532.14,1413.88 -387.43,1413.88 ; -527.21,1422.84 -396.39,1422.84 ; -521.83,1431.8 -405.8,1431.8 ; -516.46,1440.76 -406.7,1440.76 ; -511.08,1449.72 -407.59,1449.72 ; -506.6,1458.68 -408.94,1458.68 ; -500.78,1467.64 -409.83,1467.64 ; -495.85,1476.6 -410.73,1476.6 ; -491.37,1485.56 -411.62,1485.56 ; -485.99,1494.52 -412.97,1494.52 ; -481.06,1503.48 -414.31,1503.48 ; -475.24,1512.44 -415.66,1512.44 ; -470.31,1521.4 -416.55,1521.4 ; -465.38,1530.36 -411.62,1530.36 ; -460.01,1539.32 -407.59,1539.32 ; -454.63,1548.28 -415.66,1548.28 ; -449.26,1557.24 -431.78,1557.24 ; -434.92,1584.12 -379.37,1584.12 ; -429.54,1593.08 -372.2,1593.08 ; -424.62,1602.04 -366.38,1602.04 ; -423.27,1575.16 -385.64,1575.16 ; -419.24,1611 -360.1,1611 ; -414.31,1619.96 -351.14,1619.96 ; -408.94,1628.92 -341.29,1628.92 ; -406.25,1566.2 -391.46,1566.2 ; -404.9,1543.35 -416.1,1520.95 -404.9,1431.35 -371.3,1397.75 -360.1,1397.75 ccw(c-365.95,1414.55) -360.1,1431.35 -371.3,1509.75 -360.55,1519.16 ; -403.56,1637.88 -312.17,1637.88 ; -399.08,1646.84 -263.34,1646.84 ; -395.05,1560.82 -360.1,1610.55 -337.7,1632.95 -214.5,1655.35 ; -393.7,1655.8 -214.5,1655.8 ; -388.78,1664.76 -219.43,1664.76 ; -383.4,1673.72 -224.36,1673.72 ; -378.92,1682.68 -229.74,1682.68 ; -373.54,1691.64 -235.11,1691.64 ; -368.17,1700.6 -239.59,1700.6 ; -362.79,1709.56 -245.42,1709.56 ; -361.45,1440.76 -356.97,1440.76 ; -360.1,1431.8 -339.5,1431.8 ; -360.1,1442.55 -315.3,1420.15 ; -357.86,1718.52 -249.9,1718.52 ; -352.94,1727.48 -255.72,1727.48 ; -351.14,1404.92 -317.99,1404.92 ; -350.25,1422.84 -320.23,1422.84 ; -348.46,1413.88 -318.44,1413.88 ; -347.56,1736.44 -260.65,1736.44 ; -345.32,1533.94 -315.3,1543.35 -270.5,1498.55 ; -342.63,1745.4 -265.13,1745.4 ; -337.26,1754.36 -271.4,1754.36 ; -332.33,1763.32 -276.33,1763.32 ; -330.09,1502.14 -330.09,1468.54 -296.49,1446.14 ; -326.95,1772.28 -281.26,1772.28 ; -322.02,1781.24 -287.08,1781.24 ; -316.65,1790.2 -291.56,1790.2 ; -311.27,1799.16 -296.04,1799.16 ; -306.34,1808.12 -301.42,1808.12 ; -304.55,1387 -111.02,1387 ; -294.7,1395.96 -127.14,1395.96 ; -285.74,1404.92 -145.06,1404.92 ; -281.7,1408.95 -259.3,1408.95 ccw(c-269.99,1412.82) -265.58,1423.29 ; -281.26,1476.6 -281.7,1476.6 -304.1,1431.35 ccw(c-292.89,1408.95) -304.11,1386.55 -236.9,1453.75 ; -270.95,1494.97 -270.95,1498.55 ; -263.34,1422.84 -179.56,1422.84 ; -259.3,1431.35 -236.9,1431.35 ccw(c-249.11,1431.94) -244.97,1443.45 ; -257.96,1413.88 -161.19,1413.88 ; -240.94,1440.76 -213.16,1440.76 ; -240.94,1449.72 -229.29,1449.72 ; -236.46,1431.8 -195.24,1431.8 ; -222.12,1468.09 -214.5,1476.15 -192.1,1543.35 -165.22,1569.34 ; -219.43,1467.64 -106.09,1467.64 ; -214.5,1476.6 -111.91,1476.6 ; -211.37,1485.56 -116.39,1485.56 ; -208.23,1494.52 -121.77,1494.52 ; -205.1,1503.48 -127.14,1503.48 ; -202.86,1458.68 -101.16,1458.68 ; -201.96,1512.44 -132.07,1512.44 ; -199.27,1521.4 -137,1521.4 ; -195.69,1530.36 -142.82,1530.36 ; -193,1539.32 -148.2,1539.32 ; -186.28,1449.72 -96.23,1449.72 ; -186.28,1548.28 -153.13,1548.28 ; -177.32,1557.24 -157.61,1557.24 ; -168.81,1440.76 -90.41,1440.76 ; -168.36,1566.2 -162.98,1566.2 ; -152.68,1431.8 -85.03,1431.8 ; -136.1,1422.84 -81,1422.84 ; -119.53,1413.88 -76.07,1413.88 ; -102.06,1404.92 -70.7,1404.92 ; -85.48,1395.96 -65.32,1395.96 ; -68.01,1387 -59.5,1387 ; -561.26,1363.7 -445.67,1564.41 -66.22,1363.7 -561.26,1363.7 ; -436.26,1581.88 -55.91,1380.28 -304.1,1812.6 -436.26,1581.88
  text "ALL PROCESSES MUST BE ROHS COMPLIANT." at -665,1990 h60
  text "CAUTION" at 520,1787 h60
  text "THIS ASSEMBLY INCORPORATES" at 345,1712 h30
  text "STATIC SENSITIVE DEVICES" at 420,1637 h30
  text "ASSEMBLY AND HANDLING MUST BE DONE AT AN" at 145,1562 h30
  text "APPROVED STATIC FREE STATION" at 370,1487 h30
  text "CAUTION" at 545,1362 h60
  text "GND" at 110,1070 h20 r90
  text "RFOUT" at 170,1070 h20 r90
  text "GND" at 230,1070 h20 r90
  text "MGPO3" at 300,1070 h20 r90
  text "MGPO2" at 360,1070 h20 r90
  text "GND" at 420,1070 h20 r90
  text "MGPO1" at 480,1070 h20 r90
  text "MGPO0" at 540,1070 h20 r90
  text "GND" at 595,1070 h20 r90
  text "+3.3V" at 650,1070 h20 r90
  text "GND" at 710,1070 h20 r90
  text "+1.8V" at 770,1070 h20 r90
  text "GND" at 830,1070 h20 r90
  text "GND" at -945,930 h20
  text "GND" at 1115,930 h20
  text "GND" at -945,870 h20
  text "LOADENB" at 1115,870 h20
  text "GND" at -945,810 h20
  text "SDO" at 1115,810 h20
  text "RESETN" at 1115,745 h20
  text "SSN" at 1115,690 h20
  text "SCLK" at 1115,630 h20
  text "WDTENB" at 1115,570 h20
  text "GND" at 1115,510 h20
  text "EXTCLKIN" at 1115,445 h20
  text "GND" at 1115,385 h20
  text "SDI" at 1115,325 h20
  text "DGPIN1" at 1115,270 h20
  text "STATO" at 1120,210 h20
  text "GND" at -940,205 h20
  text "DGPIN0" at 1115,155 h20
  text "GND" at -940,145 h20
  text "GND" at 1120,90 h20
  text "GND" at -940,85 h20
  text "GND" at 110,-170 h20 r90
  text "RFIN" at 170,-170 h20 r90
  text "GND" at 230,-170 h20 r90
  text "GND" at 295,-170 h20 r90
  text "GND" at 355,-170 h20 r90
  text "ADCIN0P" at 415,-170 h20 r90
  text "ADCIN0N" at 475,-170 h20 r90
  text "GND" at 530,-170 h20 r90
  text "ADCIN1P" at 590,-170 h20 r90
  text "ADCIN1N" at 650,-170 h20 r90
  text "GND" at 710,-170 h20 r90
  text "RFFB" at 770,-170 h20 r90
  text "GND" at 830,-170 h20 r90
  text "ASSY TOP" at 705.91,-778.15 h50
Drill Drawing:
  lines w1: -700,1050 -699.97,1050 ; -700,1100 -700,1240 ; -26.59,1190 -700,1190 ; 326.59,1190 1000,1190 ; 985,1000 985.03,1000 ; 1000,0 1000.03,0 ; 1000,1045 1000.03,1045 ; 1000,1095 1000,1240 ; 1035,1000 1290,1000 ; 1050,0 1290,0 ; 1240,432.5 1240,0 ; 1240,567.5 1240,1000 ; 2690,-1310 2690.03,-1310 ; 2700,-380 2700.03,-380 ; -700,1190 -600,1165 -600,1215 -700,1190 ; 1000,1190 900,1215 900,1165 1000,1190 ; 1240,0 1265,100 1215,100 1240,0 ; 1240,1000 1215,900 1265,900 1240,1000 ; 2740,-1310 2740,-1260 4690,-1260 4690,-1310 2740,-1310 ; 2740,-1010 2740,-960 4690,-960 4690,-1010 2740,-1010 ; 2740,-710 2740,-660 4690,-660 4690,-710 2740,-710 ; 2740,-410 2740,-360 4690,-360 4690,-410 2740,-410 ; 2840,-1260 2840,-1010 4590,-1010 4590,-1260 2840,-1260 ; 2840,-960 2840,-710 4590,-710 4590,-960 2840,-960 ; 2840,-660 2840,-410 4590,-410 4590,-660 2840,-660
  lines w10: 2259,-1310 2640,-1310 ; 2259,-380 2650,-380 ; 2309,-1460 2309,-1310 ; 2309,-230 2309,-380 ; 2309,-1310 2284,-1410 2334,-1410 2309,-1310 ; 2309,-380 2334,-280 2284,-280 2309,-380
  text "NOTES: (UNLESS OTHERWISE SPECIFIED)" at 2210,3075 h60
  text "1) FINISHED BOARD THICKNESS TO BE 42 MILS +/- 10%." at 2190,2790 h50
  text "2) SOLDERMASK TO BE LPI, COLOR : GREEN, BOTH SIDES." at 2190,2640 h50
  text "3) PLATING:  IMMERSION GOLD OVER ELECTROLESS NICKEL." at 2190,2490 h50
  text "- ALL LAYERS USE 1 OZ COPPER." at 2340,2340 h50
  text "4) SILKSCREEN:  TOP SIDE, COLOR: WHITE" at 2190,2190 h50
  text "5) SEE DRILL CHART FOR FINISHED HOLE SIZES." at 2190,2040 h50
  text "6) HOLE TOLERANCE IS +/- 3 MILS UNLESS OTHERWISE SPECIFIED." at 2190,1890 h50
  text "7) THIS IS A 4 LAYER BOARD." at 2190,1740 h50
  text "8) TRACE WIDTHS IN ARTWORK ARE FINISHED SIZES.  DO NOT DEVIATE" at 2190,1590 h50
  text "WITHOUT PRIOR AUTHORIZATION FROM SCINTERA." at 2340,1440 h50
  text "9) BOW AND TWIST: .75% MAX ALLOWABLE." at 2190,1290 h50
  text "1700mil" at 3.41,1152.5 h50
  text "10) FABRICATE PER IPC-6012 CLASS 2 ( LATEST REVISION ) UNLESS OTHERWISE SPECIFIED." at 2190,1140 h50
  text "11) REMOVE ALL BURRS AND SHARP EDGES." at 2190,990 h50
  text "12) VENDOR SHALL PERFORM FULL NETS LIST TEST - EXTRACT NETS LIST FROM GERBER." at 2190,840 h50
  text "13) FINISHED BOARD SHALL BE RoHS COMPLIANT." at 2190,690 h50
  text "14) COPPER TO THE EDGE BY DESIGN. NO RELIEF." at 2190,540 h50
  text "1000mil" at 1093.41,462.5 h50
  text "15) REMOVE UNUSED PADS." at 2190,390 h50
  text "16) TENT ALL 10 MIL VIAS USING SOLDERMASK ON THE LAYER4." at 2190,240 h50
  text "LAYER STACK UP" at 3190,-210 h65
  text "LAYER1 TOP" at 4840,-410 h50
  text "FR406 14MIL +/- 1MIL" at 3240,-560 h50
  text "LAYER2 GND" at 4840,-710 h50
  text "RF4 PRE-PREG" at 3390,-860 h50
  text "Scintera" at 88.58,-953.35 h50
  text "LAYER3 PWR/SIG" at 4840,-1010 h50
  text "SC1894-DB1900A  FAB and DRILL DWG" at 78.74,-1084.25 h50
  text "42 +/- 4MIL" at 2340,-1110 h50 r90
  text "FR406 14MIL +/- 1MIL" at 3240,-1160 h50
  text "(RDB 3.6R2)" at 87.6,-1221.06 h50
  text "LAYER4 BOTTOM" at 4840,-1310 h50
MECH:
  the board outline again, w2
  text "41" at 75,1050 h35
  text "29" at 795,1050 h35
  text "42" at -910,920 h35
  text "28" at 1050,915 h35
  text "47" at -910,80 h35
  text "14" at 1065,75 h35
  text "1" at 90,-90 h35
  text "13" at 810,-90 h35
